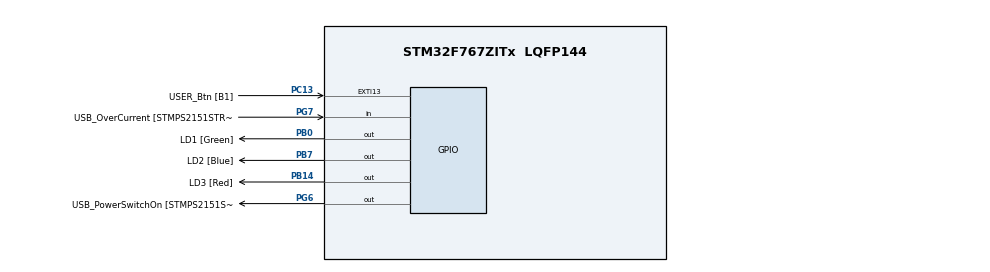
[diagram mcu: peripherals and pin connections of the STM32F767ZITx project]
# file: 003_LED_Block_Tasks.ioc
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Mcu.Family=STM32F7
Mcu.Name=STM32F767ZITx
Mcu.Package=LQFP144
NVIC.PriorityGroup=NVIC_PRIORITYGROUP_4
NVIC.TIM6_DAC_IRQn=true\:15\:0\:false\:false\:true\:false\:true\:true
NVIC.TimeBase=TIM6_DAC_IRQn
NVIC.TimeBaseIP=TIM6
PA1.GPIO_Label=RMII_REF_CLK [LAN8742A-CZ-TR_REFCLK0]
PA1.Signal=ETH_REF_CLK
PA10.GPIO_Label=USB_ID
PA10.Signal=USB_OTG_FS_ID
PA11.GPIO_Label=USB_DM
PA11.Signal=USB_OTG_FS_DM
PA12.GPIO_Label=USB_DP
PA12.Signal=USB_OTG_FS_DP
PA13.GPIO_Label=TMS
PA13.Signal=SYS_JTMS-SWDIO
PA14.GPIO_Label=TCK
PA14.Signal=SYS_JTCK-SWCLK
PA2.GPIO_Label=RMII_MDIO [LAN8742A-CZ-TR_MDIO]
PA2.Signal=ETH_MDIO
PA7.GPIO_Label=RMII_CRS_DV [LAN8742A-CZ-TR_CRS_DV]
PA7.Signal=ETH_CRS_DV
PA8.GPIO_Label=USB_SOF [TP1]
PA8.Signal=USB_OTG_FS_SOF
PA9.GPIO_Label=USB_VBUS
PA9.Signal=USB_OTG_FS_VBUS
PB0.GPIO_Label=LD1 [Green]
PB0.Signal=GPIO_Output
PB13.GPIO_Label=RMII_TXD1 [LAN8742A-CZ-TR_TXD1]
PB13.Signal=ETH_TXD1
PB14.GPIO_Label=LD3 [Red]
PB14.Signal=GPIO_Output
PB3.GPIO_Label=SW0
PB3.Signal=SYS_JTDO-SWO
PB7.GPIO_Label=LD2 [Blue]
PB7.Signal=GPIO_Output
PC1.GPIO_Label=RMII_MDC [LAN8742A-CZ-TR_MDC]
PC1.Signal=ETH_MDC
PC13.GPIO_Label=USER_Btn [B1]
PC13.Signal=GPXTI13
PC14/OSC32_IN.Signal=RCC_OSC32_IN
PC15/OSC32_OUT.Signal=RCC_OSC32_OUT
PC4.GPIO_Label=RMII_RXD0 [LAN8742A-CZ-TR_RXD0]
PC4.Signal=ETH_RXD0
PC5.GPIO_Label=RMII_RXD1 [LAN8742A-CZ-TR_RXD1]
PC5.Signal=ETH_RXD1
PD8.GPIO_Label=STLK_RX [STM32F103CBT6_PA3]
PD8.Signal=USART3_TX
PD9.GPIO_Label=STLK_TX [STM32F103CBT6_PA2]
PD9.Signal=USART3_RX
PG11.GPIO_Label=RMII_TX_EN [LAN8742A-CZ-TR_TXEN]
PG11.Signal=ETH_TX_EN
PG13.GPIO_Label=RMII_TXD0 [LAN8742A-CZ-TR_TXD0]
PG13.Signal=ETH_TXD0
PG6.GPIO_Label=USB_PowerSwitchOn [STMPS2151STR_EN]
PG6.Signal=GPIO_Output
PG7.GPIO_Label=USB_OverCurrent [STMPS2151STR_FAULT]
PG7.Signal=GPIO_Input
PH0/OSC_IN.GPIO_Label=MCO [STM32F103CBT6_PA8]
PH0/OSC_IN.Signal=RCC_OSC_IN
PH1/OSC_OUT.Signal=RCC_OSC_OUT
ProjectManager.HeapSize=0x200
ProjectManager.StackSize=0x400
ProjectManager.TargetToolchain=STM32CubeIDE
RCC.48MHZClocksFreq_Value=24000000
RCC.AHBFreq_Value=16000000
RCC.APB1CLKDivider=RCC_HCLK_DIV2
RCC.APB1Freq_Value=8000000
RCC.APB1TimFreq_Value=16000000
RCC.APB2Freq_Value=16000000
RCC.APB2TimFreq_Value=16000000
RCC.CortexFreq_Value=16000000
RCC.HCLKFreq_Value=16000000
RCC.HSE_VALUE=16000000
RCC.HSI_VALUE=16000000
RCC.LSE_VALUE=32768
RCC.PLLMUL=RCC_PLL_MUL9
RCC.PRESCALERUSB=RCC_USBCLKSOURCE_PLL_DIV1_5
RCC.SYSCLKFreq_VALUE=16000000
RCC.SYSCLKSourceVirtual=RCC_SYSCLKSOURCE_PLLCLK
RCC.USBFreq_Value=96000000
RCC.VCOOutputFreq_Value=192000000
VP_SYS_VS_tim6.Mode=TIM6
board=NUCLEO-F767ZI

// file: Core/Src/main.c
/* USER CODE BEGIN Header */
/**
 ******************************************************************************
 * @file           : main.c
 * @brief          : Main program body
 ******************************************************************************
 * @attention
 *
 * Copyright (c) 2025 STMicroelectronics.
 * All rights reserved.
 *
 * This software is licensed under terms that can be found in the LICENSE file
 * in the root directory of this software component.
 * If no LICENSE file comes with this software, it is provided AS-IS.
 *
 ******************************************************************************
 */
/* USER CODE END Header */
#include "main.h"

/* USER CODE BEGIN Includes */
#include "stdio.h"
#include "FreeRTOS.h"
#include "task.h"

/* USER CODE END Includes */

/* USER CODE BEGIN PV */
#define DWT_CTRL					 (*(volatile uint32_t *)0xE0001000)

/* USER CODE END PV */

void SystemClock_Config(void);
static void MX_GPIO_Init(void);
/* USER CODE BEGIN PFP */
static void led_green_handler(void* parameters);
static void led_red_handler(void* parameters);
static void led_blue_handler(void* parameters);

/* USER CODE END PFP */

int main(void)
{

  /* USER CODE BEGIN 1 */
	TaskHandle_t task1_handle;
	TaskHandle_t task2_handle;
	TaskHandle_t task3_handle;

	BaseType_t status;

  /* USER CODE END 1 */

  /* MCU Configuration--------------------------------------------------------*/

  /* Reset of all peripherals, Initializes the Flash interface and the Systick. */
  HAL_Init();

  /* Configure the system clock */
  SystemClock_Config();

  /* Initialize all configured peripherals */
  MX_GPIO_Init();
  /* USER CODE BEGIN 2 */
	/* Enable the CYcle counting */
	DWT_CTRL |= (1 << 0);

	SEGGER_UART_init(250000);

	SEGGER_SYSVIEW_Conf();
	//SEGGER_SYSVIEW_Start();

	status = xTaskCreate(led_green_handler, "LED_Green_Task", 200, NULL, 2, &task1_handle);

	configASSERT(status = pdPASS);

	status = xTaskCreate(led_red_handler, "LED_Red_Task", 200, NULL, 2, &task2_handle);

	configASSERT(status = pdPASS);

	status = xTaskCreate(led_blue_handler, "LED_Blue_Task", 200, NULL, 2, &task3_handle);

	configASSERT(status = pdPASS);

	//STart the FreeRTOS Scheduler
	vTaskStartScheduler();

  /* USER CODE END 2 */

  /* Infinite loop */
	while (1)
	{

	}
}

void SystemClock_Config(void)
{
  RCC_OscInitTypeDef RCC_OscInitStruct = {0};
  RCC_ClkInitTypeDef RCC_ClkInitStruct = {0};

  /** Configure the main internal regulator output voltage
  */
  __HAL_RCC_PWR_CLK_ENABLE();
  __HAL_PWR_VOLTAGESCALING_CONFIG(PWR_REGULATOR_VOLTAGE_SCALE2);

  /** Initializes the RCC Oscillators according to the specified parameters
  * in the RCC_OscInitTypeDef structure.
  */
  RCC_OscInitStruct.OscillatorType = RCC_OSCILLATORTYPE_HSI;
  RCC_OscInitStruct.HSIState = RCC_HSI_ON;
  RCC_OscInitStruct.HSICalibrationValue = RCC_HSICALIBRATION_DEFAULT;
  RCC_OscInitStruct.PLL.PLLState = RCC_PLL_ON;
  RCC_OscInitStruct.PLL.PLLSource = RCC_PLLSOURCE_HSI;
  RCC_OscInitStruct.PLL.PLLM = 8;
  RCC_OscInitStruct.PLL.PLLN = 168;
  RCC_OscInitStruct.PLL.PLLP = RCC_PLLP_DIV2;
  RCC_OscInitStruct.PLL.PLLQ = 2;
  RCC_OscInitStruct.PLL.PLLR = 2;
  if (HAL_RCC_OscConfig(&RCC_OscInitStruct) != HAL_OK)
  {
    Error_Handler();
  }

  /** Initializes the CPU, AHB and APB buses clocks
  */
  RCC_ClkInitStruct.ClockType = RCC_CLOCKTYPE_HCLK|RCC_CLOCKTYPE_SYSCLK
                              |RCC_CLOCKTYPE_PCLK1|RCC_CLOCKTYPE_PCLK2;
  RCC_ClkInitStruct.SYSCLKSource = RCC_SYSCLKSOURCE_PLLCLK;
  RCC_ClkInitStruct.AHBCLKDivider = RCC_SYSCLK_DIV1;
  RCC_ClkInitStruct.APB1CLKDivider = RCC_HCLK_DIV4;
  RCC_ClkInitStruct.APB2CLKDivider = RCC_HCLK_DIV2;

  if (HAL_RCC_ClockConfig(&RCC_ClkInitStruct, FLASH_LATENCY_5) != HAL_OK)
  {
    Error_Handler();
  }
}

static void MX_GPIO_Init(void)
{
  GPIO_InitTypeDef GPIO_InitStruct = {0};

  /* GPIO Ports Clock Enable */
  __HAL_RCC_GPIOC_CLK_ENABLE();
  __HAL_RCC_GPIOH_CLK_ENABLE();
  __HAL_RCC_GPIOA_CLK_ENABLE();
  __HAL_RCC_GPIOB_CLK_ENABLE();
  __HAL_RCC_GPIOD_CLK_ENABLE();
  __HAL_RCC_GPIOG_CLK_ENABLE();

  /*Configure GPIO pin Output Level */
  HAL_GPIO_WritePin(GPIOB, LD1_Pin|LD3_Pin|LD2_Pin, GPIO_PIN_RESET);

  /*Configure GPIO pin Output Level */
  HAL_GPIO_WritePin(USB_PowerSwitchOn_GPIO_Port, USB_PowerSwitchOn_Pin, GPIO_PIN_RESET);

  /*Configure GPIO pin : USER_Btn_Pin */
  GPIO_InitStruct.Pin = USER_Btn_Pin;
  GPIO_InitStruct.Mode = GPIO_MODE_IT_RISING;
  GPIO_InitStruct.Pull = GPIO_NOPULL;
  HAL_GPIO_Init(USER_Btn_GPIO_Port, &GPIO_InitStruct);

  /*Configure GPIO pins : RMII_MDC_Pin RMII_RXD0_Pin RMII_RXD1_Pin */
  GPIO_InitStruct.Pin = RMII_MDC_Pin|RMII_RXD0_Pin|RMII_RXD1_Pin;
  GPIO_InitStruct.Mode = GPIO_MODE_AF_PP;
  GPIO_InitStruct.Pull = GPIO_NOPULL;
  GPIO_InitStruct.Speed = GPIO_SPEED_FREQ_VERY_HIGH;
  GPIO_InitStruct.Alternate = GPIO_AF11_ETH;
  HAL_GPIO_Init(GPIOC, &GPIO_InitStruct);

  /*Configure GPIO pins : RMII_REF_CLK_Pin RMII_MDIO_Pin RMII_CRS_DV_Pin */
  GPIO_InitStruct.Pin = RMII_REF_CLK_Pin|RMII_MDIO_Pin|RMII_CRS_DV_Pin;
  GPIO_InitStruct.Mode = GPIO_MODE_AF_PP;
  GPIO_InitStruct.Pull = GPIO_NOPULL;
  GPIO_InitStruct.Speed = GPIO_SPEED_FREQ_VERY_HIGH;
  GPIO_InitStruct.Alternate = GPIO_AF11_ETH;
  HAL_GPIO_Init(GPIOA, &GPIO_InitStruct);

  /*Configure GPIO pins : LD1_Pin LD3_Pin LD2_Pin */
  GPIO_InitStruct.Pin = LD1_Pin|LD3_Pin|LD2_Pin;
  GPIO_InitStruct.Mode = GPIO_MODE_OUTPUT_PP;
  GPIO_InitStruct.Pull = GPIO_NOPULL;
  GPIO_InitStruct.Speed = GPIO_SPEED_FREQ_LOW;
  HAL_GPIO_Init(GPIOB, &GPIO_InitStruct);

  /*Configure GPIO pin : RMII_TXD1_Pin */
  GPIO_InitStruct.Pin = RMII_TXD1_Pin;
  GPIO_InitStruct.Mode = GPIO_MODE_AF_PP;
  GPIO_InitStruct.Pull = GPIO_NOPULL;
  GPIO_InitStruct.Speed = GPIO_SPEED_FREQ_VERY_HIGH;
  GPIO_InitStruct.Alternate = GPIO_AF11_ETH;
  HAL_GPIO_Init(RMII_TXD1_GPIO_Port, &GPIO_InitStruct);

  /*Configure GPIO pins : STLK_RX_Pin STLK_TX_Pin */
  GPIO_InitStruct.Pin = STLK_RX_Pin|STLK_TX_Pin;
  GPIO_InitStruct.Mode = GPIO_MODE_AF_PP;
  GPIO_InitStruct.Pull = GPIO_NOPULL;
  GPIO_InitStruct.Speed = GPIO_SPEED_FREQ_VERY_HIGH;
  GPIO_InitStruct.Alternate = GPIO_AF7_USART3;
  HAL_GPIO_Init(GPIOD, &GPIO_InitStruct);

  /*Configure GPIO pin : USB_PowerSwitchOn_Pin */
  GPIO_InitStruct.Pin = USB_PowerSwitchOn_Pin;
  GPIO_InitStruct.Mode = GPIO_MODE_OUTPUT_PP;
  GPIO_InitStruct.Pull = GPIO_NOPULL;
  GPIO_InitStruct.Speed = GPIO_SPEED_FREQ_LOW;
  HAL_GPIO_Init(USB_PowerSwitchOn_GPIO_Port, &GPIO_InitStruct);

  /*Configure GPIO pin : USB_OverCurrent_Pin */
  GPIO_InitStruct.Pin = USB_OverCurrent_Pin;
  GPIO_InitStruct.Mode = GPIO_MODE_INPUT;
  GPIO_InitStruct.Pull = GPIO_NOPULL;
  HAL_GPIO_Init(USB_OverCurrent_GPIO_Port, &GPIO_InitStruct);

  /*Configure GPIO pins : USB_SOF_Pin USB_ID_Pin USB_DM_Pin USB_DP_Pin */
  GPIO_InitStruct.Pin = USB_SOF_Pin|USB_ID_Pin|USB_DM_Pin|USB_DP_Pin;
  GPIO_InitStruct.Mode = GPIO_MODE_AF_PP;
  GPIO_InitStruct.Pull = GPIO_NOPULL;
  GPIO_InitStruct.Speed = GPIO_SPEED_FREQ_VERY_HIGH;
  GPIO_InitStruct.Alternate = GPIO_AF10_OTG_FS;
  HAL_GPIO_Init(GPIOA, &GPIO_InitStruct);

  /*Configure GPIO pin : USB_VBUS_Pin */
  GPIO_InitStruct.Pin = USB_VBUS_Pin;
  GPIO_InitStruct.Mode = GPIO_MODE_INPUT;
  GPIO_InitStruct.Pull = GPIO_NOPULL;
  HAL_GPIO_Init(USB_VBUS_GPIO_Port, &GPIO_InitStruct);

  /*Configure GPIO pins : RMII_TX_EN_Pin RMII_TXD0_Pin */
  GPIO_InitStruct.Pin = RMII_TX_EN_Pin|RMII_TXD0_Pin;
  GPIO_InitStruct.Mode = GPIO_MODE_AF_PP;
  GPIO_InitStruct.Pull = GPIO_NOPULL;
  GPIO_InitStruct.Speed = GPIO_SPEED_FREQ_VERY_HIGH;
  GPIO_InitStruct.Alternate = GPIO_AF11_ETH;
  HAL_GPIO_Init(GPIOG, &GPIO_InitStruct);

}

/* USER CODE BEGIN 4 */

static void led_green_handler(void* parameters)
{
	while (1)
	{
		HAL_GPIO_TogglePin(GPIOB, LD1_Pin);
		vTaskDelay(pdMS_TO_TICKS(1000));
		//HAL_Delay(1000);
		SEGGER_SYSVIEW_PrintfTarget("Toggle Green LED");
	}

}

static void led_red_handler(void* parameters)
{
	while(1)
	{
		HAL_GPIO_TogglePin(GPIOB, LD3_Pin);
		vTaskDelay(pdMS_TO_TICKS(400));
		//HAL_Delay(400);
		SEGGER_SYSVIEW_PrintfTarget("Toggle Red LED");
	}
}

static void led_blue_handler(void* parameters)
{
	while(1)
	{
		HAL_GPIO_TogglePin(GPIOB, LD2_Pin);
		vTaskDelay(pdMS_TO_TICKS(800));
		//HAL_Delay(800);
		SEGGER_SYSVIEW_PrintfTarget("Toggle Blue LED");
	}

}

void vApplicationIdleHook (void)
{
	HAL_PWR_EnterSLEEPMode(PWR_MAINREGULATOR_ON, PWR_SLEEPENTRY_WFI);
}

/* USER CODE END 4 */

void HAL_TIM_PeriodElapsedCallback(TIM_HandleTypeDef *htim)
{
  if (htim->Instance == TIM6) {
    HAL_IncTick();
  }
}

void Error_Handler(void)
{
	__disable_irq();
	while (1)
	{
	}
}
